# Generated by FakeRAM 2.0
VERSION 5.7 ;
BUSBITCHARS "[]" ;
PROPERTYDEFINITIONS
  MACRO width INTEGER ;
  MACRO depth INTEGER ;
  MACRO banks INTEGER ;
END PROPERTYDEFINITIONS
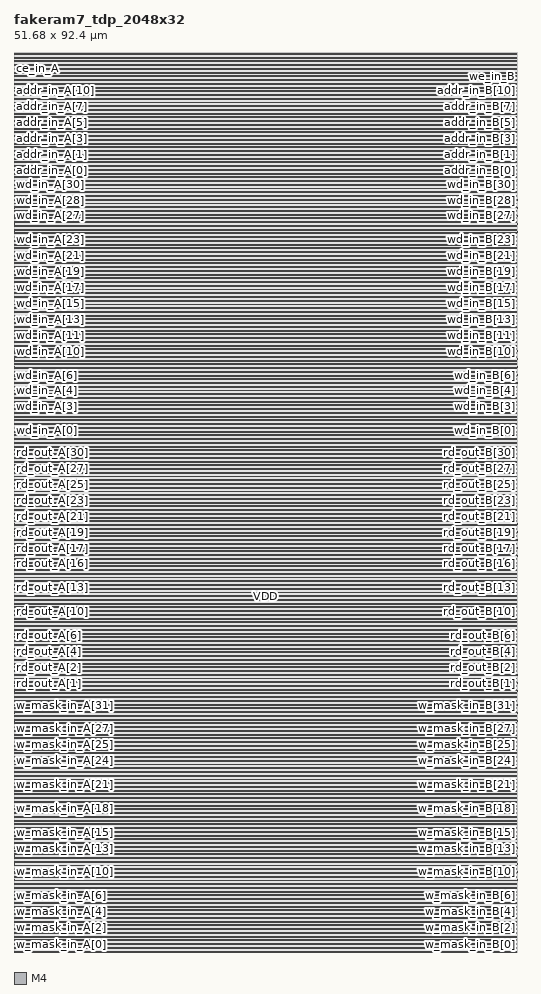
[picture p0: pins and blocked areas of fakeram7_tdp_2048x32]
MACRO fakeram7_tdp_2048x32
  PROPERTY width 32 ;
  PROPERTY depth 2048 ;
  PROPERTY banks 8 ;
  FOREIGN fakeram7_tdp_2048x32 0 0 ;
  SYMMETRY X Y ;
  SIZE 51.680 BY 92.400 ;
  CLASS BLOCK ;
  PIN w_mask_in_A[0]
    DIRECTION INPUT ;
    USE SIGNAL ;
    SHAPE ABUTMENT ;
    PORT
      LAYER M4 ;
      RECT 0.000 0.048 0.024 0.072 ;
    END
  END w_mask_in_A[0]
  PIN w_mask_in_B[0]
    DIRECTION INPUT ;
    USE SIGNAL ;
    SHAPE ABUTMENT ;
    PORT
      LAYER M4 ;
      RECT 51.656 0.048 51.680 0.072 ;
    END
  END w_mask_in_B[0]
  PIN w_mask_in_A[1]
    DIRECTION INPUT ;
    USE SIGNAL ;
    SHAPE ABUTMENT ;
    PORT
      LAYER M4 ;
      RECT 0.000 0.864 0.024 0.888 ;
    END
  END w_mask_in_A[1]
  PIN w_mask_in_B[1]
    DIRECTION INPUT ;
    USE SIGNAL ;
    SHAPE ABUTMENT ;
    PORT
      LAYER M4 ;
      RECT 51.656 0.864 51.680 0.888 ;
    END
  END w_mask_in_B[1]
  PIN w_mask_in_A[2]
    DIRECTION INPUT ;
    USE SIGNAL ;
    SHAPE ABUTMENT ;
    PORT
      LAYER M4 ;
      RECT 0.000 1.680 0.024 1.704 ;
    END
  END w_mask_in_A[2]
  PIN w_mask_in_B[2]
    DIRECTION INPUT ;
    USE SIGNAL ;
    SHAPE ABUTMENT ;
    PORT
      LAYER M4 ;
      RECT 51.656 1.680 51.680 1.704 ;
    END
  END w_mask_in_B[2]
  PIN w_mask_in_A[3]
    DIRECTION INPUT ;
    USE SIGNAL ;
    SHAPE ABUTMENT ;
    PORT
      LAYER M4 ;
      RECT 0.000 2.496 0.024 2.520 ;
    END
  END w_mask_in_A[3]
  PIN w_mask_in_B[3]
    DIRECTION INPUT ;
    USE SIGNAL ;
    SHAPE ABUTMENT ;
    PORT
      LAYER M4 ;
      RECT 51.656 2.496 51.680 2.520 ;
    END
  END w_mask_in_B[3]
  PIN w_mask_in_A[4]
    DIRECTION INPUT ;
    USE SIGNAL ;
    SHAPE ABUTMENT ;
    PORT
      LAYER M4 ;
      RECT 0.000 3.312 0.024 3.336 ;
    END
  END w_mask_in_A[4]
  PIN w_mask_in_B[4]
    DIRECTION INPUT ;
    USE SIGNAL ;
    SHAPE ABUTMENT ;
    PORT
      LAYER M4 ;
      RECT 51.656 3.312 51.680 3.336 ;
    END
  END w_mask_in_B[4]
  PIN w_mask_in_A[5]
    DIRECTION INPUT ;
    USE SIGNAL ;
    SHAPE ABUTMENT ;
    PORT
      LAYER M4 ;
      RECT 0.000 4.128 0.024 4.152 ;
    END
  END w_mask_in_A[5]
  PIN w_mask_in_B[5]
    DIRECTION INPUT ;
    USE SIGNAL ;
    SHAPE ABUTMENT ;
    PORT
      LAYER M4 ;
      RECT 51.656 4.128 51.680 4.152 ;
    END
  END w_mask_in_B[5]
  PIN w_mask_in_A[6]
    DIRECTION INPUT ;
    USE SIGNAL ;
    SHAPE ABUTMENT ;
    PORT
      LAYER M4 ;
      RECT 0.000 4.944 0.024 4.968 ;
    END
  END w_mask_in_A[6]
  PIN w_mask_in_B[6]
    DIRECTION INPUT ;
    USE SIGNAL ;
    SHAPE ABUTMENT ;
    PORT
      LAYER M4 ;
      RECT 51.656 4.944 51.680 4.968 ;
    END
  END w_mask_in_B[6]
  PIN w_mask_in_A[7]
    DIRECTION INPUT ;
    USE SIGNAL ;
    SHAPE ABUTMENT ;
    PORT
      LAYER M4 ;
      RECT 0.000 5.760 0.024 5.784 ;
    END
  END w_mask_in_A[7]
  PIN w_mask_in_B[7]
    DIRECTION INPUT ;
    USE SIGNAL ;
    SHAPE ABUTMENT ;
    PORT
      LAYER M4 ;
      RECT 51.656 5.760 51.680 5.784 ;
    END
  END w_mask_in_B[7]
  PIN w_mask_in_A[8]
    DIRECTION INPUT ;
    USE SIGNAL ;
    SHAPE ABUTMENT ;
    PORT
      LAYER M4 ;
      RECT 0.000 6.576 0.024 6.600 ;
    END
  END w_mask_in_A[8]
  PIN w_mask_in_B[8]
    DIRECTION INPUT ;
    USE SIGNAL ;
    SHAPE ABUTMENT ;
    PORT
      LAYER M4 ;
      RECT 51.656 6.576 51.680 6.600 ;
    END
  END w_mask_in_B[8]
  PIN w_mask_in_A[9]
    DIRECTION INPUT ;
    USE SIGNAL ;
    SHAPE ABUTMENT ;
    PORT
      LAYER M4 ;
      RECT 0.000 7.392 0.024 7.416 ;
    END
  END w_mask_in_A[9]
  PIN w_mask_in_B[9]
    DIRECTION INPUT ;
    USE SIGNAL ;
    SHAPE ABUTMENT ;
    PORT
      LAYER M4 ;
      RECT 51.656 7.392 51.680 7.416 ;
    END
  END w_mask_in_B[9]
  PIN w_mask_in_A[10]
    DIRECTION INPUT ;
    USE SIGNAL ;
    SHAPE ABUTMENT ;
    PORT
      LAYER M4 ;
      RECT 0.000 8.208 0.024 8.232 ;
    END
  END w_mask_in_A[10]
  PIN w_mask_in_B[10]
    DIRECTION INPUT ;
    USE SIGNAL ;
    SHAPE ABUTMENT ;
    PORT
      LAYER M4 ;
      RECT 51.656 8.208 51.680 8.232 ;
    END
  END w_mask_in_B[10]
  PIN w_mask_in_A[11]
    DIRECTION INPUT ;
    USE SIGNAL ;
    SHAPE ABUTMENT ;
    PORT
      LAYER M4 ;
      RECT 0.000 9.024 0.024 9.048 ;
    END
  END w_mask_in_A[11]
  PIN w_mask_in_B[11]
    DIRECTION INPUT ;
    USE SIGNAL ;
    SHAPE ABUTMENT ;
    PORT
      LAYER M4 ;
      RECT 51.656 9.024 51.680 9.048 ;
    END
  END w_mask_in_B[11]
  PIN w_mask_in_A[12]
    DIRECTION INPUT ;
    USE SIGNAL ;
    SHAPE ABUTMENT ;
    PORT
      LAYER M4 ;
      RECT 0.000 9.840 0.024 9.864 ;
    END
  END w_mask_in_A[12]
  PIN w_mask_in_B[12]
    DIRECTION INPUT ;
    USE SIGNAL ;
    SHAPE ABUTMENT ;
    PORT
      LAYER M4 ;
      RECT 51.656 9.840 51.680 9.864 ;
    END
  END w_mask_in_B[12]
  PIN w_mask_in_A[13]
    DIRECTION INPUT ;
    USE SIGNAL ;
    SHAPE ABUTMENT ;
    PORT
      LAYER M4 ;
      RECT 0.000 10.656 0.024 10.680 ;
    END
  END w_mask_in_A[13]
  PIN w_mask_in_B[13]
    DIRECTION INPUT ;
    USE SIGNAL ;
    SHAPE ABUTMENT ;
    PORT
      LAYER M4 ;
      RECT 51.656 10.656 51.680 10.680 ;
    END
  END w_mask_in_B[13]
  PIN w_mask_in_A[14]
    DIRECTION INPUT ;
    USE SIGNAL ;
    SHAPE ABUTMENT ;
    PORT
      LAYER M4 ;
      RECT 0.000 11.472 0.024 11.496 ;
    END
  END w_mask_in_A[14]
  PIN w_mask_in_B[14]
    DIRECTION INPUT ;
    USE SIGNAL ;
    SHAPE ABUTMENT ;
    PORT
      LAYER M4 ;
      RECT 51.656 11.472 51.680 11.496 ;
    END
  END w_mask_in_B[14]
  PIN w_mask_in_A[15]
    DIRECTION INPUT ;
    USE SIGNAL ;
    SHAPE ABUTMENT ;
    PORT
      LAYER M4 ;
      RECT 0.000 12.288 0.024 12.312 ;
    END
  END w_mask_in_A[15]
  PIN w_mask_in_B[15]
    DIRECTION INPUT ;
    USE SIGNAL ;
    SHAPE ABUTMENT ;
    PORT
      LAYER M4 ;
      RECT 51.656 12.288 51.680 12.312 ;
    END
  END w_mask_in_B[15]
  PIN w_mask_in_A[16]
    DIRECTION INPUT ;
    USE SIGNAL ;
    SHAPE ABUTMENT ;
    PORT
      LAYER M4 ;
      RECT 0.000 13.104 0.024 13.128 ;
    END
  END w_mask_in_A[16]
  PIN w_mask_in_B[16]
    DIRECTION INPUT ;
    USE SIGNAL ;
    SHAPE ABUTMENT ;
    PORT
      LAYER M4 ;
      RECT 51.656 13.104 51.680 13.128 ;
    END
  END w_mask_in_B[16]
  PIN w_mask_in_A[17]
    DIRECTION INPUT ;
    USE SIGNAL ;
    SHAPE ABUTMENT ;
    PORT
      LAYER M4 ;
      RECT 0.000 13.920 0.024 13.944 ;
    END
  END w_mask_in_A[17]
  PIN w_mask_in_B[17]
    DIRECTION INPUT ;
    USE SIGNAL ;
    SHAPE ABUTMENT ;
    PORT
      LAYER M4 ;
      RECT 51.656 13.920 51.680 13.944 ;
    END
  END w_mask_in_B[17]
  PIN w_mask_in_A[18]
    DIRECTION INPUT ;
    USE SIGNAL ;
    SHAPE ABUTMENT ;
    PORT
      LAYER M4 ;
      RECT 0.000 14.736 0.024 14.760 ;
    END
  END w_mask_in_A[18]
  PIN w_mask_in_B[18]
    DIRECTION INPUT ;
    USE SIGNAL ;
    SHAPE ABUTMENT ;
    PORT
      LAYER M4 ;
      RECT 51.656 14.736 51.680 14.760 ;
    END
  END w_mask_in_B[18]
  PIN w_mask_in_A[19]
    DIRECTION INPUT ;
    USE SIGNAL ;
    SHAPE ABUTMENT ;
    PORT
      LAYER M4 ;
      RECT 0.000 15.552 0.024 15.576 ;
    END
  END w_mask_in_A[19]
  PIN w_mask_in_B[19]
    DIRECTION INPUT ;
    USE SIGNAL ;
    SHAPE ABUTMENT ;
    PORT
      LAYER M4 ;
      RECT 51.656 15.552 51.680 15.576 ;
    END
  END w_mask_in_B[19]
  PIN w_mask_in_A[20]
    DIRECTION INPUT ;
    USE SIGNAL ;
    SHAPE ABUTMENT ;
    PORT
      LAYER M4 ;
      RECT 0.000 16.368 0.024 16.392 ;
    END
  END w_mask_in_A[20]
  PIN w_mask_in_B[20]
    DIRECTION INPUT ;
    USE SIGNAL ;
    SHAPE ABUTMENT ;
    PORT
      LAYER M4 ;
      RECT 51.656 16.368 51.680 16.392 ;
    END
  END w_mask_in_B[20]
  PIN w_mask_in_A[21]
    DIRECTION INPUT ;
    USE SIGNAL ;
    SHAPE ABUTMENT ;
    PORT
      LAYER M4 ;
      RECT 0.000 17.184 0.024 17.208 ;
    END
  END w_mask_in_A[21]
  PIN w_mask_in_B[21]
    DIRECTION INPUT ;
    USE SIGNAL ;
    SHAPE ABUTMENT ;
    PORT
      LAYER M4 ;
      RECT 51.656 17.184 51.680 17.208 ;
    END
  END w_mask_in_B[21]
  PIN w_mask_in_A[22]
    DIRECTION INPUT ;
    USE SIGNAL ;
    SHAPE ABUTMENT ;
    PORT
      LAYER M4 ;
      RECT 0.000 18.000 0.024 18.024 ;
    END
  END w_mask_in_A[22]
  PIN w_mask_in_B[22]
    DIRECTION INPUT ;
    USE SIGNAL ;
    SHAPE ABUTMENT ;
    PORT
      LAYER M4 ;
      RECT 51.656 18.000 51.680 18.024 ;
    END
  END w_mask_in_B[22]
  PIN w_mask_in_A[23]
    DIRECTION INPUT ;
    USE SIGNAL ;
    SHAPE ABUTMENT ;
    PORT
      LAYER M4 ;
      RECT 0.000 18.816 0.024 18.840 ;
    END
  END w_mask_in_A[23]
  PIN w_mask_in_B[23]
    DIRECTION INPUT ;
    USE SIGNAL ;
    SHAPE ABUTMENT ;
    PORT
      LAYER M4 ;
      RECT 51.656 18.816 51.680 18.840 ;
    END
  END w_mask_in_B[23]
  PIN w_mask_in_A[24]
    DIRECTION INPUT ;
    USE SIGNAL ;
    SHAPE ABUTMENT ;
    PORT
      LAYER M4 ;
      RECT 0.000 19.632 0.024 19.656 ;
    END
  END w_mask_in_A[24]
  PIN w_mask_in_B[24]
    DIRECTION INPUT ;
    USE SIGNAL ;
    SHAPE ABUTMENT ;
    PORT
      LAYER M4 ;
      RECT 51.656 19.632 51.680 19.656 ;
    END
  END w_mask_in_B[24]
  PIN w_mask_in_A[25]
    DIRECTION INPUT ;
    USE SIGNAL ;
    SHAPE ABUTMENT ;
    PORT
      LAYER M4 ;
      RECT 0.000 20.448 0.024 20.472 ;
    END
  END w_mask_in_A[25]
  PIN w_mask_in_B[25]
    DIRECTION INPUT ;
    USE SIGNAL ;
    SHAPE ABUTMENT ;
    PORT
      LAYER M4 ;
      RECT 51.656 20.448 51.680 20.472 ;
    END
  END w_mask_in_B[25]
  PIN w_mask_in_A[26]
    DIRECTION INPUT ;
    USE SIGNAL ;
    SHAPE ABUTMENT ;
    PORT
      LAYER M4 ;
      RECT 0.000 21.264 0.024 21.288 ;
    END
  END w_mask_in_A[26]
  PIN w_mask_in_B[26]
    DIRECTION INPUT ;
    USE SIGNAL ;
    SHAPE ABUTMENT ;
    PORT
      LAYER M4 ;
      RECT 51.656 21.264 51.680 21.288 ;
    END
  END w_mask_in_B[26]
  PIN w_mask_in_A[27]
    DIRECTION INPUT ;
    USE SIGNAL ;
    SHAPE ABUTMENT ;
    PORT
      LAYER M4 ;
      RECT 0.000 22.080 0.024 22.104 ;
    END
  END w_mask_in_A[27]
  PIN w_mask_in_B[27]
    DIRECTION INPUT ;
    USE SIGNAL ;
    SHAPE ABUTMENT ;
    PORT
      LAYER M4 ;
      RECT 51.656 22.080 51.680 22.104 ;
    END
  END w_mask_in_B[27]
  PIN w_mask_in_A[28]
    DIRECTION INPUT ;
    USE SIGNAL ;
    SHAPE ABUTMENT ;
    PORT
      LAYER M4 ;
      RECT 0.000 22.896 0.024 22.920 ;
    END
  END w_mask_in_A[28]
  PIN w_mask_in_B[28]
    DIRECTION INPUT ;
    USE SIGNAL ;
    SHAPE ABUTMENT ;
    PORT
      LAYER M4 ;
      RECT 51.656 22.896 51.680 22.920 ;
    END
  END w_mask_in_B[28]
  PIN w_mask_in_A[29]
    DIRECTION INPUT ;
    USE SIGNAL ;
    SHAPE ABUTMENT ;
    PORT
      LAYER M4 ;
      RECT 0.000 23.712 0.024 23.736 ;
    END
  END w_mask_in_A[29]
  PIN w_mask_in_B[29]
    DIRECTION INPUT ;
    USE SIGNAL ;
    SHAPE ABUTMENT ;
    PORT
      LAYER M4 ;
      RECT 51.656 23.712 51.680 23.736 ;
    END
  END w_mask_in_B[29]
  PIN w_mask_in_A[30]
    DIRECTION INPUT ;
    USE SIGNAL ;
    SHAPE ABUTMENT ;
    PORT
      LAYER M4 ;
      RECT 0.000 24.528 0.024 24.552 ;
    END
  END w_mask_in_A[30]
  PIN w_mask_in_B[30]
    DIRECTION INPUT ;
    USE SIGNAL ;
    SHAPE ABUTMENT ;
    PORT
      LAYER M4 ;
      RECT 51.656 24.528 51.680 24.552 ;
    END
  END w_mask_in_B[30]
  PIN w_mask_in_A[31]
    DIRECTION INPUT ;
    USE SIGNAL ;
    SHAPE ABUTMENT ;
    PORT
      LAYER M4 ;
      RECT 0.000 25.344 0.024 25.368 ;
    END
  END w_mask_in_A[31]
  PIN w_mask_in_B[31]
    DIRECTION INPUT ;
    USE SIGNAL ;
    SHAPE ABUTMENT ;
    PORT
      LAYER M4 ;
      RECT 51.656 25.344 51.680 25.368 ;
    END
  END w_mask_in_B[31]
  PIN rd_out_A[0]
    DIRECTION OUTPUT ;
    USE SIGNAL ;
    SHAPE ABUTMENT ;
    PORT
      LAYER M4 ;
      RECT 0.000 26.784 0.024 26.808 ;
    END
  END rd_out_A[0]
  PIN rd_out_B[0]
    DIRECTION OUTPUT ;
    USE SIGNAL ;
    SHAPE ABUTMENT ;
    PORT
      LAYER M4 ;
      RECT 51.656 26.784 51.680 26.808 ;
    END
  END rd_out_B[0]
  PIN rd_out_A[1]
    DIRECTION OUTPUT ;
    USE SIGNAL ;
    SHAPE ABUTMENT ;
    PORT
      LAYER M4 ;
      RECT 0.000 27.600 0.024 27.624 ;
    END
  END rd_out_A[1]
  PIN rd_out_B[1]
    DIRECTION OUTPUT ;
    USE SIGNAL ;
    SHAPE ABUTMENT ;
    PORT
      LAYER M4 ;
      RECT 51.656 27.600 51.680 27.624 ;
    END
  END rd_out_B[1]
  PIN rd_out_A[2]
    DIRECTION OUTPUT ;
    USE SIGNAL ;
    SHAPE ABUTMENT ;
    PORT
      LAYER M4 ;
      RECT 0.000 28.416 0.024 28.440 ;
    END
  END rd_out_A[2]
  PIN rd_out_B[2]
    DIRECTION OUTPUT ;
    USE SIGNAL ;
    SHAPE ABUTMENT ;
    PORT
      LAYER M4 ;
      RECT 51.656 28.416 51.680 28.440 ;
    END
  END rd_out_B[2]
  PIN rd_out_A[3]
    DIRECTION OUTPUT ;
    USE SIGNAL ;
    SHAPE ABUTMENT ;
    PORT
      LAYER M4 ;
      RECT 0.000 29.232 0.024 29.256 ;
    END
  END rd_out_A[3]
  PIN rd_out_B[3]
    DIRECTION OUTPUT ;
    USE SIGNAL ;
    SHAPE ABUTMENT ;
    PORT
      LAYER M4 ;
      RECT 51.656 29.232 51.680 29.256 ;
    END
  END rd_out_B[3]
  PIN rd_out_A[4]
    DIRECTION OUTPUT ;
    USE SIGNAL ;
    SHAPE ABUTMENT ;
    PORT
      LAYER M4 ;
      RECT 0.000 30.048 0.024 30.072 ;
    END
  END rd_out_A[4]
  PIN rd_out_B[4]
    DIRECTION OUTPUT ;
    USE SIGNAL ;
    SHAPE ABUTMENT ;
    PORT
      LAYER M4 ;
      RECT 51.656 30.048 51.680 30.072 ;
    END
  END rd_out_B[4]
  PIN rd_out_A[5]
    DIRECTION OUTPUT ;
    USE SIGNAL ;
    SHAPE ABUTMENT ;
    PORT
      LAYER M4 ;
      RECT 0.000 30.864 0.024 30.888 ;
    END
  END rd_out_A[5]
  PIN rd_out_B[5]
    DIRECTION OUTPUT ;
    USE SIGNAL ;
    SHAPE ABUTMENT ;
    PORT
      LAYER M4 ;
      RECT 51.656 30.864 51.680 30.888 ;
    END
  END rd_out_B[5]
  PIN rd_out_A[6]
    DIRECTION OUTPUT ;
    USE SIGNAL ;
    SHAPE ABUTMENT ;
    PORT
      LAYER M4 ;
      RECT 0.000 31.680 0.024 31.704 ;
    END
  END rd_out_A[6]
  PIN rd_out_B[6]
    DIRECTION OUTPUT ;
    USE SIGNAL ;
    SHAPE ABUTMENT ;
    PORT
      LAYER M4 ;
      RECT 51.656 31.680 51.680 31.704 ;
    END
  END rd_out_B[6]
  PIN rd_out_A[7]
    DIRECTION OUTPUT ;
    USE SIGNAL ;
    SHAPE ABUTMENT ;
    PORT
      LAYER M4 ;
      RECT 0.000 32.496 0.024 32.520 ;
    END
  END rd_out_A[7]
  PIN rd_out_B[7]
    DIRECTION OUTPUT ;
    USE SIGNAL ;
    SHAPE ABUTMENT ;
    PORT
      LAYER M4 ;
      RECT 51.656 32.496 51.680 32.520 ;
    END
  END rd_out_B[7]
  PIN rd_out_A[8]
    DIRECTION OUTPUT ;
    USE SIGNAL ;
    SHAPE ABUTMENT ;
    PORT
      LAYER M4 ;
      RECT 0.000 33.312 0.024 33.336 ;
    END
  END rd_out_A[8]
  PIN rd_out_B[8]
    DIRECTION OUTPUT ;
    USE SIGNAL ;
    SHAPE ABUTMENT ;
    PORT
      LAYER M4 ;
      RECT 51.656 33.312 51.680 33.336 ;
    END
  END rd_out_B[8]
  PIN rd_out_A[9]
    DIRECTION OUTPUT ;
    USE SIGNAL ;
    SHAPE ABUTMENT ;
    PORT
      LAYER M4 ;
      RECT 0.000 34.128 0.024 34.152 ;
    END
  END rd_out_A[9]
  PIN rd_out_B[9]
    DIRECTION OUTPUT ;
    USE SIGNAL ;
    SHAPE ABUTMENT ;
    PORT
      LAYER M4 ;
      RECT 51.656 34.128 51.680 34.152 ;
    END
  END rd_out_B[9]
  PIN rd_out_A[10]
    DIRECTION OUTPUT ;
    USE SIGNAL ;
    SHAPE ABUTMENT ;
    PORT
      LAYER M4 ;
      RECT 0.000 34.944 0.024 34.968 ;
    END
  END rd_out_A[10]
  PIN rd_out_B[10]
    DIRECTION OUTPUT ;
    USE SIGNAL ;
    SHAPE ABUTMENT ;
    PORT
      LAYER M4 ;
      RECT 51.656 34.944 51.680 34.968 ;
    END
  END rd_out_B[10]
  PIN rd_out_A[11]
    DIRECTION OUTPUT ;
    USE SIGNAL ;
    SHAPE ABUTMENT ;
    PORT
      LAYER M4 ;
      RECT 0.000 35.760 0.024 35.784 ;
    END
  END rd_out_A[11]
  PIN rd_out_B[11]
    DIRECTION OUTPUT ;
    USE SIGNAL ;
    SHAPE ABUTMENT ;
    PORT
      LAYER M4 ;
      RECT 51.656 35.760 51.680 35.784 ;
    END
  END rd_out_B[11]
  PIN rd_out_A[12]
    DIRECTION OUTPUT ;
    USE SIGNAL ;
    SHAPE ABUTMENT ;
    PORT
      LAYER M4 ;
      RECT 0.000 36.576 0.024 36.600 ;
    END
  END rd_out_A[12]
  PIN rd_out_B[12]
    DIRECTION OUTPUT ;
    USE SIGNAL ;
    SHAPE ABUTMENT ;
    PORT
      LAYER M4 ;
      RECT 51.656 36.576 51.680 36.600 ;
    END
  END rd_out_B[12]
  PIN rd_out_A[13]
    DIRECTION OUTPUT ;
    USE SIGNAL ;
    SHAPE ABUTMENT ;
    PORT
      LAYER M4 ;
      RECT 0.000 37.392 0.024 37.416 ;
    END
  END rd_out_A[13]
  PIN rd_out_B[13]
    DIRECTION OUTPUT ;
    USE SIGNAL ;
    SHAPE ABUTMENT ;
    PORT
      LAYER M4 ;
      RECT 51.656 37.392 51.680 37.416 ;
    END
  END rd_out_B[13]
  PIN rd_out_A[14]
    DIRECTION OUTPUT ;
    USE SIGNAL ;
    SHAPE ABUTMENT ;
    PORT
      LAYER M4 ;
      RECT 0.000 38.208 0.024 38.232 ;
    END
  END rd_out_A[14]
  PIN rd_out_B[14]
    DIRECTION OUTPUT ;
    USE SIGNAL ;
    SHAPE ABUTMENT ;
    PORT
      LAYER M4 ;
      RECT 51.656 38.208 51.680 38.232 ;
    END
  END rd_out_B[14]
  PIN rd_out_A[15]
    DIRECTION OUTPUT ;
    USE SIGNAL ;
    SHAPE ABUTMENT ;
    PORT
      LAYER M4 ;
      RECT 0.000 39.024 0.024 39.048 ;
    END
  END rd_out_A[15]
  PIN rd_out_B[15]
    DIRECTION OUTPUT ;
    USE SIGNAL ;
    SHAPE ABUTMENT ;
    PORT
      LAYER M4 ;
      RECT 51.656 39.024 51.680 39.048 ;
    END
  END rd_out_B[15]
  PIN rd_out_A[16]
    DIRECTION OUTPUT ;
    USE SIGNAL ;
    SHAPE ABUTMENT ;
    PORT
      LAYER M4 ;
      RECT 0.000 39.840 0.024 39.864 ;
    END
  END rd_out_A[16]
  PIN rd_out_B[16]
    DIRECTION OUTPUT ;
    USE SIGNAL ;
    SHAPE ABUTMENT ;
    PORT
      LAYER M4 ;
      RECT 51.656 39.840 51.680 39.864 ;
    END
  END rd_out_B[16]
  PIN rd_out_A[17]
    DIRECTION OUTPUT ;
    USE SIGNAL ;
    SHAPE ABUTMENT ;
    PORT
      LAYER M4 ;
      RECT 0.000 40.656 0.024 40.680 ;
    END
  END rd_out_A[17]
  PIN rd_out_B[17]
    DIRECTION OUTPUT ;
    USE SIGNAL ;
    SHAPE ABUTMENT ;
    PORT
      LAYER M4 ;
      RECT 51.656 40.656 51.680 40.680 ;
    END
  END rd_out_B[17]
  PIN rd_out_A[18]
    DIRECTION OUTPUT ;
    USE SIGNAL ;
    SHAPE ABUTMENT ;
    PORT
      LAYER M4 ;
      RECT 0.000 41.472 0.024 41.496 ;
    END
  END rd_out_A[18]
  PIN rd_out_B[18]
    DIRECTION OUTPUT ;
    USE SIGNAL ;
    SHAPE ABUTMENT ;
    PORT
      LAYER M4 ;
      RECT 51.656 41.472 51.680 41.496 ;
    END
  END rd_out_B[18]
  PIN rd_out_A[19]
    DIRECTION OUTPUT ;
    USE SIGNAL ;
    SHAPE ABUTMENT ;
    PORT
      LAYER M4 ;
      RECT 0.000 42.288 0.024 42.312 ;
    END
  END rd_out_A[19]
  PIN rd_out_B[19]
    DIRECTION OUTPUT ;
    USE SIGNAL ;
    SHAPE ABUTMENT ;
    PORT
      LAYER M4 ;
      RECT 51.656 42.288 51.680 42.312 ;
    END
  END rd_out_B[19]
  PIN rd_out_A[20]
    DIRECTION OUTPUT ;
    USE SIGNAL ;
    SHAPE ABUTMENT ;
    PORT
      LAYER M4 ;
      RECT 0.000 43.104 0.024 43.128 ;
    END
  END rd_out_A[20]
  PIN rd_out_B[20]
    DIRECTION OUTPUT ;
    USE SIGNAL ;
    SHAPE ABUTMENT ;
    PORT
      LAYER M4 ;
      RECT 51.656 43.104 51.680 43.128 ;
    END
  END rd_out_B[20]
  PIN rd_out_A[21]
    DIRECTION OUTPUT ;
    USE SIGNAL ;
    SHAPE ABUTMENT ;
    PORT
      LAYER M4 ;
      RECT 0.000 43.920 0.024 43.944 ;
    END
  END rd_out_A[21]
  PIN rd_out_B[21]
    DIRECTION OUTPUT ;
    USE SIGNAL ;
    SHAPE ABUTMENT ;
    PORT
      LAYER M4 ;
      RECT 51.656 43.920 51.680 43.944 ;
    END
  END rd_out_B[21]
  PIN rd_out_A[22]
    DIRECTION OUTPUT ;
    USE SIGNAL ;
    SHAPE ABUTMENT ;
    PORT
      LAYER M4 ;
      RECT 0.000 44.736 0.024 44.760 ;
    END
  END rd_out_A[22]
  PIN rd_out_B[22]
    DIRECTION OUTPUT ;
    USE SIGNAL ;
    SHAPE ABUTMENT ;
    PORT
      LAYER M4 ;
      RECT 51.656 44.736 51.680 44.760 ;
    END
  END rd_out_B[22]
  PIN rd_out_A[23]
    DIRECTION OUTPUT ;
    USE SIGNAL ;
    SHAPE ABUTMENT ;
    PORT
      LAYER M4 ;
      RECT 0.000 45.552 0.024 45.576 ;
    END
  END rd_out_A[23]
  PIN rd_out_B[23]
    DIRECTION OUTPUT ;
    USE SIGNAL ;
    SHAPE ABUTMENT ;
    PORT
      LAYER M4 ;
      RECT 51.656 45.552 51.680 45.576 ;
    END
  END rd_out_B[23]
  PIN rd_out_A[24]
    DIRECTION OUTPUT ;
    USE SIGNAL ;
    SHAPE ABUTMENT ;
    PORT
      LAYER M4 ;
      RECT 0.000 46.368 0.024 46.392 ;
    END
  END rd_out_A[24]
  PIN rd_out_B[24]
    DIRECTION OUTPUT ;
    USE SIGNAL ;
    SHAPE ABUTMENT ;
    PORT
      LAYER M4 ;
      RECT 51.656 46.368 51.680 46.392 ;
    END
  END rd_out_B[24]
  PIN rd_out_A[25]
    DIRECTION OUTPUT ;
    USE SIGNAL ;
    SHAPE ABUTMENT ;
    PORT
      LAYER M4 ;
      RECT 0.000 47.184 0.024 47.208 ;
    END
  END rd_out_A[25]
  PIN rd_out_B[25]
    DIRECTION OUTPUT ;
    USE SIGNAL ;
    SHAPE ABUTMENT ;
    PORT
      LAYER M4 ;
      RECT 51.656 47.184 51.680 47.208 ;
    END
  END rd_out_B[25]
  PIN rd_out_A[26]
    DIRECTION OUTPUT ;
    USE SIGNAL ;
    SHAPE ABUTMENT ;
    PORT
      LAYER M4 ;
      RECT 0.000 48.000 0.024 48.024 ;
    END
  END rd_out_A[26]
  PIN rd_out_B[26]
    DIRECTION OUTPUT ;
    USE SIGNAL ;
    SHAPE ABUTMENT ;
    PORT
      LAYER M4 ;
      RECT 51.656 48.000 51.680 48.024 ;
    END
  END rd_out_B[26]
  PIN rd_out_A[27]
    DIRECTION OUTPUT ;
    USE SIGNAL ;
    SHAPE ABUTMENT ;
    PORT
      LAYER M4 ;
      RECT 0.000 48.816 0.024 48.840 ;
    END
  END rd_out_A[27]
  PIN rd_out_B[27]
    DIRECTION OUTPUT ;
    USE SIGNAL ;
    SHAPE ABUTMENT ;
    PORT
      LAYER M4 ;
      RECT 51.656 48.816 51.680 48.840 ;
    END
  END rd_out_B[27]
  PIN rd_out_A[28]
    DIRECTION OUTPUT ;
    USE SIGNAL ;
    SHAPE ABUTMENT ;
    PORT
      LAYER M4 ;
      RECT 0.000 49.632 0.024 49.656 ;
    END
  END rd_out_A[28]
  PIN rd_out_B[28]
    DIRECTION OUTPUT ;
    USE SIGNAL ;
    SHAPE ABUTMENT ;
    PORT
      LAYER M4 ;
      RECT 51.656 49.632 51.680 49.656 ;
    END
  END rd_out_B[28]
  PIN rd_out_A[29]
    DIRECTION OUTPUT ;
    USE SIGNAL ;
    SHAPE ABUTMENT ;
    PORT
      LAYER M4 ;
      RECT 0.000 50.448 0.024 50.472 ;
    END
  END rd_out_A[29]
  PIN rd_out_B[29]
    DIRECTION OUTPUT ;
    USE SIGNAL ;
    SHAPE ABUTMENT ;
    PORT
      LAYER M4 ;
      RECT 51.656 50.448 51.680 50.472 ;
    END
  END rd_out_B[29]
  PIN rd_out_A[30]
    DIRECTION OUTPUT ;
    USE SIGNAL ;
    SHAPE ABUTMENT ;
    PORT
      LAYER M4 ;
      RECT 0.000 51.264 0.024 51.288 ;
    END
  END rd_out_A[30]
  PIN rd_out_B[30]
    DIRECTION OUTPUT ;
    USE SIGNAL ;
    SHAPE ABUTMENT ;
    PORT
      LAYER M4 ;
      RECT 51.656 51.264 51.680 51.288 ;
    END
  END rd_out_B[30]
  PIN rd_out_A[31]
    DIRECTION OUTPUT ;
    USE SIGNAL ;
    SHAPE ABUTMENT ;
    PORT
      LAYER M4 ;
      RECT 0.000 52.080 0.024 52.104 ;
    END
  END rd_out_A[31]
  PIN rd_out_B[31]
    DIRECTION OUTPUT ;
    USE SIGNAL ;
    SHAPE ABUTMENT ;
    PORT
      LAYER M4 ;
      RECT 51.656 52.080 51.680 52.104 ;
    END
  END rd_out_B[31]
  PIN wd_in_A[0]
    DIRECTION INPUT ;
    USE SIGNAL ;
    SHAPE ABUTMENT ;
    PORT
      LAYER M4 ;
      RECT 0.000 53.520 0.024 53.544 ;
    END
  END wd_in_A[0]
  PIN wd_in_B[0]
    DIRECTION INPUT ;
    USE SIGNAL ;
    SHAPE ABUTMENT ;
    PORT
      LAYER M4 ;
      RECT 51.656 53.520 51.680 53.544 ;
    END
  END wd_in_B[0]
  PIN wd_in_A[1]
    DIRECTION INPUT ;
    USE SIGNAL ;
    SHAPE ABUTMENT ;
    PORT
      LAYER M4 ;
      RECT 0.000 54.336 0.024 54.360 ;
    END
  END wd_in_A[1]
  PIN wd_in_B[1]
    DIRECTION INPUT ;
    USE SIGNAL ;
    SHAPE ABUTMENT ;
    PORT
      LAYER M4 ;
      RECT 51.656 54.336 51.680 54.360 ;
    END
  END wd_in_B[1]
  PIN wd_in_A[2]
    DIRECTION INPUT ;
    USE SIGNAL ;
    SHAPE ABUTMENT ;
    PORT
      LAYER M4 ;
      RECT 0.000 55.152 0.024 55.176 ;
    END
  END wd_in_A[2]
  PIN wd_in_B[2]
    DIRECTION INPUT ;
    USE SIGNAL ;
    SHAPE ABUTMENT ;
    PORT
      LAYER M4 ;
      RECT 51.656 55.152 51.680 55.176 ;
    END
  END wd_in_B[2]
  PIN wd_in_A[3]
    DIRECTION INPUT ;
    USE SIGNAL ;
    SHAPE ABUTMENT ;
    PORT
      LAYER M4 ;
      RECT 0.000 55.968 0.024 55.992 ;
    END
  END wd_in_A[3]
  PIN wd_in_B[3]
    DIRECTION INPUT ;
    USE SIGNAL ;
    SHAPE ABUTMENT ;
    PORT
      LAYER M4 ;
      RECT 51.656 55.968 51.680 55.992 ;
    END
  END wd_in_B[3]
  PIN wd_in_A[4]
    DIRECTION INPUT ;
    USE SIGNAL ;
    SHAPE ABUTMENT ;
    PORT
      LAYER M4 ;
      RECT 0.000 56.784 0.024 56.808 ;
    END
  END wd_in_A[4]
  PIN wd_in_B[4]
    DIRECTION INPUT ;
    USE SIGNAL ;
    SHAPE ABUTMENT ;
    PORT
      LAYER M4 ;
      RECT 51.656 56.784 51.680 56.808 ;
    END
  END wd_in_B[4]
  PIN wd_in_A[5]
    DIRECTION INPUT ;
    USE SIGNAL ;
    SHAPE ABUTMENT ;
    PORT
      LAYER M4 ;
      RECT 0.000 57.600 0.024 57.624 ;
    END
  END wd_in_A[5]
  PIN wd_in_B[5]
    DIRECTION INPUT ;
    USE SIGNAL ;
    SHAPE ABUTMENT ;
    PORT
      LAYER M4 ;
      RECT 51.656 57.600 51.680 57.624 ;
    END
  END wd_in_B[5]
  PIN wd_in_A[6]
    DIRECTION INPUT ;
    USE SIGNAL ;
    SHAPE ABUTMENT ;
    PORT
      LAYER M4 ;
      RECT 0.000 58.416 0.024 58.440 ;
    END
  END wd_in_A[6]
  PIN wd_in_B[6]
    DIRECTION INPUT ;
    USE SIGNAL ;
    SHAPE ABUTMENT ;
    PORT
      LAYER M4 ;
      RECT 51.656 58.416 51.680 58.440 ;
    END
  END wd_in_B[6]
  PIN wd_in_A[7]
    DIRECTION INPUT ;
    USE SIGNAL ;
    SHAPE ABUTMENT ;
    PORT
      LAYER M4 ;
      RECT 0.000 59.232 0.024 59.256 ;
    END
  END wd_in_A[7]
  PIN wd_in_B[7]
    DIRECTION INPUT ;
    USE SIGNAL ;
    SHAPE ABUTMENT ;
    PORT
      LAYER M4 ;
      RECT 51.656 59.232 51.680 59.256 ;
    END
  END wd_in_B[7]
  PIN wd_in_A[8]
    DIRECTION INPUT ;
    USE SIGNAL ;
    SHAPE ABUTMENT ;
    PORT
      LAYER M4 ;
      RECT 0.000 60.048 0.024 60.072 ;
    END
  END wd_in_A[8]
  PIN wd_in_B[8]
    DIRECTION INPUT ;
    USE SIGNAL ;
    SHAPE ABUTMENT ;
    PORT
      LAYER M4 ;
      RECT 51.656 60.048 51.680 60.072 ;
    END
  END wd_in_B[8]
  PIN wd_in_A[9]
    DIRECTION INPUT ;
    USE SIGNAL ;
    SHAPE ABUTMENT ;
    PORT
      LAYER M4 ;
      RECT 0.000 60.864 0.024 60.888 ;
    END
  END wd_in_A[9]
  PIN wd_in_B[9]
    DIRECTION INPUT ;
    USE SIGNAL ;
    SHAPE ABUTMENT ;
    PORT
      LAYER M4 ;
      RECT 51.656 60.864 51.680 60.888 ;
    END
  END wd_in_B[9]
  PIN wd_in_A[10]
    DIRECTION INPUT ;
    USE SIGNAL ;
    SHAPE ABUTMENT ;
    PORT
      LAYER M4 ;
      RECT 0.000 61.680 0.024 61.704 ;
    END
  END wd_in_A[10]
  PIN wd_in_B[10]
    DIRECTION INPUT ;
    USE SIGNAL ;
    SHAPE ABUTMENT ;
    PORT
      LAYER M4 ;
      RECT 51.656 61.680 51.680 61.704 ;
    END
  END wd_in_B[10]
  PIN wd_in_A[11]
    DIRECTION INPUT ;
    USE SIGNAL ;
    SHAPE ABUTMENT ;
    PORT
      LAYER M4 ;
      RECT 0.000 62.496 0.024 62.520 ;
    END
  END wd_in_A[11]
  PIN wd_in_B[11]
    DIRECTION INPUT ;
    USE SIGNAL ;
    SHAPE ABUTMENT ;
    PORT
      LAYER M4 ;
      RECT 51.656 62.496 51.680 62.520 ;
    END
  END wd_in_B[11]
  PIN wd_in_A[12]
    DIRECTION INPUT ;
    USE SIGNAL ;
    SHAPE ABUTMENT ;
    PORT
      LAYER M4 ;
      RECT 0.000 63.312 0.024 63.336 ;
    END
  END wd_in_A[12]
  PIN wd_in_B[12]
    DIRECTION INPUT ;
    USE SIGNAL ;
    SHAPE ABUTMENT ;
    PORT
      LAYER M4 ;
      RECT 51.656 63.312 51.680 63.336 ;
    END
  END wd_in_B[12]
  PIN wd_in_A[13]
    DIRECTION INPUT ;
    USE SIGNAL ;
    SHAPE ABUTMENT ;
    PORT
      LAYER M4 ;
      RECT 0.000 64.128 0.024 64.152 ;
    END
  END wd_in_A[13]
  PIN wd_in_B[13]
    DIRECTION INPUT ;
    USE SIGNAL ;
    SHAPE ABUTMENT ;
    PORT
      LAYER M4 ;
      RECT 51.656 64.128 51.680 64.152 ;
    END
  END wd_in_B[13]
  PIN wd_in_A[14]
    DIRECTION INPUT ;
    USE SIGNAL ;
    SHAPE ABUTMENT ;
    PORT
      LAYER M4 ;
      RECT 0.000 64.944 0.024 64.968 ;
    END
  END wd_in_A[14]
  PIN wd_in_B[14]
    DIRECTION INPUT ;
    USE SIGNAL ;
    SHAPE ABUTMENT ;
    PORT
      LAYER M4 ;
      RECT 51.656 64.944 51.680 64.968 ;
    END
  END wd_in_B[14]
  PIN wd_in_A[15]
    DIRECTION INPUT ;
    USE SIGNAL ;
    SHAPE ABUTMENT ;
    PORT
      LAYER M4 ;
      RECT 0.000 65.760 0.024 65.784 ;
    END
  END wd_in_A[15]
  PIN wd_in_B[15]
    DIRECTION INPUT ;
    USE SIGNAL ;
    SHAPE ABUTMENT ;
    PORT
      LAYER M4 ;
      RECT 51.656 65.760 51.680 65.784 ;
    END
  END wd_in_B[15]
  PIN wd_in_A[16]
    DIRECTION INPUT ;
    USE SIGNAL ;
    SHAPE ABUTMENT ;
    PORT
      LAYER M4 ;
      RECT 0.000 66.576 0.024 66.600 ;
    END
  END wd_in_A[16]
  PIN wd_in_B[16]
    DIRECTION INPUT ;
    USE SIGNAL ;
    SHAPE ABUTMENT ;
    PORT
      LAYER M4 ;
      RECT 51.656 66.576 51.680 66.600 ;
    END
  END wd_in_B[16]
  PIN wd_in_A[17]
    DIRECTION INPUT ;
    USE SIGNAL ;
    SHAPE ABUTMENT ;
    PORT
      LAYER M4 ;
      RECT 0.000 67.392 0.024 67.416 ;
    END
  END wd_in_A[17]
  PIN wd_in_B[17]
    DIRECTION INPUT ;
    USE SIGNAL ;
    SHAPE ABUTMENT ;
    PORT
      LAYER M4 ;
      RECT 51.656 67.392 51.680 67.416 ;
    END
  END wd_in_B[17]
  PIN wd_in_A[18]
    DIRECTION INPUT ;
    USE SIGNAL ;
    SHAPE ABUTMENT ;
    PORT
      LAYER M4 ;
      RECT 0.000 68.208 0.024 68.232 ;
    END
  END wd_in_A[18]
  PIN wd_in_B[18]
    DIRECTION INPUT ;
    USE SIGNAL ;
    SHAPE ABUTMENT ;
    PORT
      LAYER M4 ;
      RECT 51.656 68.208 51.680 68.232 ;
    END
  END wd_in_B[18]
  PIN wd_in_A[19]
    DIRECTION INPUT ;
    USE SIGNAL ;
    SHAPE ABUTMENT ;
    PORT
      LAYER M4 ;
      RECT 0.000 69.024 0.024 69.048 ;
    END
  END wd_in_A[19]
  PIN wd_in_B[19]
    DIRECTION INPUT ;
    USE SIGNAL ;
    SHAPE ABUTMENT ;
    PORT
      LAYER M4 ;
      RECT 51.656 69.024 51.680 69.048 ;
    END
  END wd_in_B[19]
  PIN wd_in_A[20]
    DIRECTION INPUT ;
    USE SIGNAL ;
    SHAPE ABUTMENT ;
    PORT
      LAYER M4 ;
      RECT 0.000 69.840 0.024 69.864 ;
    END
  END wd_in_A[20]
  PIN wd_in_B[20]
    DIRECTION INPUT ;
    USE SIGNAL ;
    SHAPE ABUTMENT ;
    PORT
      LAYER M4 ;
      RECT 51.656 69.840 51.680 69.864 ;
    END
  END wd_in_B[20]
  PIN wd_in_A[21]
    DIRECTION INPUT ;
    USE SIGNAL ;
    SHAPE ABUTMENT ;
    PORT
      LAYER M4 ;
      RECT 0.000 70.656 0.024 70.680 ;
    END
  END wd_in_A[21]
  PIN wd_in_B[21]
    DIRECTION INPUT ;
    USE SIGNAL ;
    SHAPE ABUTMENT ;
    PORT
      LAYER M4 ;
      RECT 51.656 70.656 51.680 70.680 ;
    END
  END wd_in_B[21]
  PIN wd_in_A[22]
    DIRECTION INPUT ;
    USE SIGNAL ;
    SHAPE ABUTMENT ;
    PORT
      LAYER M4 ;
      RECT 0.000 71.472 0.024 71.496 ;
    END
  END wd_in_A[22]
  PIN wd_in_B[22]
    DIRECTION INPUT ;
    USE SIGNAL ;
    SHAPE ABUTMENT ;
    PORT
      LAYER M4 ;
      RECT 51.656 71.472 51.680 71.496 ;
    END
  END wd_in_B[22]
  PIN wd_in_A[23]
    DIRECTION INPUT ;
    USE SIGNAL ;
    SHAPE ABUTMENT ;
    PORT
      LAYER M4 ;
      RECT 0.000 72.288 0.024 72.312 ;
    END
  END wd_in_A[23]
  PIN wd_in_B[23]
    DIRECTION INPUT ;
    USE SIGNAL ;
    SHAPE ABUTMENT ;
    PORT
      LAYER M4 ;
      RECT 51.656 72.288 51.680 72.312 ;
    END
  END wd_in_B[23]
  PIN wd_in_A[24]
    DIRECTION INPUT ;
    USE SIGNAL ;
    SHAPE ABUTMENT ;
    PORT
      LAYER M4 ;
      RECT 0.000 73.104 0.024 73.128 ;
    END
  END wd_in_A[24]
  PIN wd_in_B[24]
    DIRECTION INPUT ;
    USE SIGNAL ;
    SHAPE ABUTMENT ;
    PORT
      LAYER M4 ;
      RECT 51.656 73.104 51.680 73.128 ;
    END
  END wd_in_B[24]
  PIN wd_in_A[25]
    DIRECTION INPUT ;
    USE SIGNAL ;
    SHAPE ABUTMENT ;
    PORT
      LAYER M4 ;
      RECT 0.000 73.920 0.024 73.944 ;
    END
  END wd_in_A[25]
  PIN wd_in_B[25]
    DIRECTION INPUT ;
    USE SIGNAL ;
    SHAPE ABUTMENT ;
    PORT
      LAYER M4 ;
      RECT 51.656 73.920 51.680 73.944 ;
    END
  END wd_in_B[25]
  PIN wd_in_A[26]
    DIRECTION INPUT ;
    USE SIGNAL ;
    SHAPE ABUTMENT ;
    PORT
      LAYER M4 ;
      RECT 0.000 74.736 0.024 74.760 ;
    END
  END wd_in_A[26]
  PIN wd_in_B[26]
    DIRECTION INPUT ;
    USE SIGNAL ;
    SHAPE ABUTMENT ;
    PORT
      LAYER M4 ;
      RECT 51.656 74.736 51.680 74.760 ;
    END
  END wd_in_B[26]
  PIN wd_in_A[27]
    DIRECTION INPUT ;
    USE SIGNAL ;
    SHAPE ABUTMENT ;
    PORT
      LAYER M4 ;
      RECT 0.000 75.552 0.024 75.576 ;
    END
  END wd_in_A[27]
  PIN wd_in_B[27]
    DIRECTION INPUT ;
    USE SIGNAL ;
    SHAPE ABUTMENT ;
    PORT
      LAYER M4 ;
      RECT 51.656 75.552 51.680 75.576 ;
    END
  END wd_in_B[27]
  PIN wd_in_A[28]
    DIRECTION INPUT ;
    USE SIGNAL ;
    SHAPE ABUTMENT ;
    PORT
      LAYER M4 ;
      RECT 0.000 76.368 0.024 76.392 ;
    END
  END wd_in_A[28]
  PIN wd_in_B[28]
    DIRECTION INPUT ;
    USE SIGNAL ;
    SHAPE ABUTMENT ;
    PORT
      LAYER M4 ;
      RECT 51.656 76.368 51.680 76.392 ;
    END
  END wd_in_B[28]
  PIN wd_in_A[29]
    DIRECTION INPUT ;
    USE SIGNAL ;
    SHAPE ABUTMENT ;
    PORT
      LAYER M4 ;
      RECT 0.000 77.184 0.024 77.208 ;
    END
  END wd_in_A[29]
  PIN wd_in_B[29]
    DIRECTION INPUT ;
    USE SIGNAL ;
    SHAPE ABUTMENT ;
    PORT
      LAYER M4 ;
      RECT 51.656 77.184 51.680 77.208 ;
    END
  END wd_in_B[29]
  PIN wd_in_A[30]
    DIRECTION INPUT ;
    USE SIGNAL ;
    SHAPE ABUTMENT ;
    PORT
      LAYER M4 ;
      RECT 0.000 78.000 0.024 78.024 ;
    END
  END wd_in_A[30]
  PIN wd_in_B[30]
    DIRECTION INPUT ;
    USE SIGNAL ;
    SHAPE ABUTMENT ;
    PORT
      LAYER M4 ;
      RECT 51.656 78.000 51.680 78.024 ;
    END
  END wd_in_B[30]
  PIN wd_in_A[31]
    DIRECTION INPUT ;
    USE SIGNAL ;
    SHAPE ABUTMENT ;
    PORT
      LAYER M4 ;
      RECT 0.000 78.816 0.024 78.840 ;
    END
  END wd_in_A[31]
  PIN wd_in_B[31]
    DIRECTION INPUT ;
    USE SIGNAL ;
    SHAPE ABUTMENT ;
    PORT
      LAYER M4 ;
      RECT 51.656 78.816 51.680 78.840 ;
    END
  END wd_in_B[31]
  PIN addr_in_A[0]
    DIRECTION INPUT ;
    USE SIGNAL ;
    SHAPE ABUTMENT ;
    PORT
      LAYER M4 ;
      RECT 0.000 80.256 0.024 80.280 ;
    END
  END addr_in_A[0]
  PIN addr_in_B[0]
    DIRECTION INPUT ;
    USE SIGNAL ;
    SHAPE ABUTMENT ;
    PORT
      LAYER M4 ;
      RECT 51.656 80.256 51.680 80.280 ;
    END
  END addr_in_B[0]
  PIN addr_in_A[1]
    DIRECTION INPUT ;
    USE SIGNAL ;
    SHAPE ABUTMENT ;
    PORT
      LAYER M4 ;
      RECT 0.000 81.072 0.024 81.096 ;
    END
  END addr_in_A[1]
  PIN addr_in_B[1]
    DIRECTION INPUT ;
    USE SIGNAL ;
    SHAPE ABUTMENT ;
    PORT
      LAYER M4 ;
      RECT 51.656 81.072 51.680 81.096 ;
    END
  END addr_in_B[1]
  PIN addr_in_A[2]
    DIRECTION INPUT ;
    USE SIGNAL ;
    SHAPE ABUTMENT ;
    PORT
      LAYER M4 ;
      RECT 0.000 81.888 0.024 81.912 ;
    END
  END addr_in_A[2]
  PIN addr_in_B[2]
    DIRECTION INPUT ;
    USE SIGNAL ;
    SHAPE ABUTMENT ;
    PORT
      LAYER M4 ;
      RECT 51.656 81.888 51.680 81.912 ;
    END
  END addr_in_B[2]
  PIN addr_in_A[3]
    DIRECTION INPUT ;
    USE SIGNAL ;
    SHAPE ABUTMENT ;
    PORT
      LAYER M4 ;
      RECT 0.000 82.704 0.024 82.728 ;
    END
  END addr_in_A[3]
  PIN addr_in_B[3]
    DIRECTION INPUT ;
    USE SIGNAL ;
    SHAPE ABUTMENT ;
    PORT
      LAYER M4 ;
      RECT 51.656 82.704 51.680 82.728 ;
    END
  END addr_in_B[3]
  PIN addr_in_A[4]
    DIRECTION INPUT ;
    USE SIGNAL ;
    SHAPE ABUTMENT ;
    PORT
      LAYER M4 ;
      RECT 0.000 83.520 0.024 83.544 ;
    END
  END addr_in_A[4]
  PIN addr_in_B[4]
    DIRECTION INPUT ;
    USE SIGNAL ;
    SHAPE ABUTMENT ;
    PORT
      LAYER M4 ;
      RECT 51.656 83.520 51.680 83.544 ;
    END
  END addr_in_B[4]
  PIN addr_in_A[5]
    DIRECTION INPUT ;
    USE SIGNAL ;
    SHAPE ABUTMENT ;
    PORT
      LAYER M4 ;
      RECT 0.000 84.336 0.024 84.360 ;
    END
  END addr_in_A[5]
  PIN addr_in_B[5]
    DIRECTION INPUT ;
    USE SIGNAL ;
    SHAPE ABUTMENT ;
    PORT
      LAYER M4 ;
      RECT 51.656 84.336 51.680 84.360 ;
    END
  END addr_in_B[5]
  PIN addr_in_A[6]
    DIRECTION INPUT ;
    USE SIGNAL ;
    SHAPE ABUTMENT ;
    PORT
      LAYER M4 ;
      RECT 0.000 85.152 0.024 85.176 ;
    END
  END addr_in_A[6]
  PIN addr_in_B[6]
    DIRECTION INPUT ;
    USE SIGNAL ;
    SHAPE ABUTMENT ;
    PORT
      LAYER M4 ;
      RECT 51.656 85.152 51.680 85.176 ;
    END
  END addr_in_B[6]
  PIN addr_in_A[7]
    DIRECTION INPUT ;
    USE SIGNAL ;
    SHAPE ABUTMENT ;
    PORT
      LAYER M4 ;
      RECT 0.000 85.968 0.024 85.992 ;
    END
  END addr_in_A[7]
  PIN addr_in_B[7]
    DIRECTION INPUT ;
    USE SIGNAL ;
    SHAPE ABUTMENT ;
    PORT
      LAYER M4 ;
      RECT 51.656 85.968 51.680 85.992 ;
    END
  END addr_in_B[7]
  PIN addr_in_A[8]
    DIRECTION INPUT ;
    USE SIGNAL ;
    SHAPE ABUTMENT ;
    PORT
      LAYER M4 ;
      RECT 0.000 86.784 0.024 86.808 ;
    END
  END addr_in_A[8]
  PIN addr_in_B[8]
    DIRECTION INPUT ;
    USE SIGNAL ;
    SHAPE ABUTMENT ;
    PORT
      LAYER M4 ;
      RECT 51.656 86.784 51.680 86.808 ;
    END
  END addr_in_B[8]
  PIN addr_in_A[9]
    DIRECTION INPUT ;
    USE SIGNAL ;
    SHAPE ABUTMENT ;
    PORT
      LAYER M4 ;
      RECT 0.000 87.600 0.024 87.624 ;
    END
  END addr_in_A[9]
  PIN addr_in_B[9]
    DIRECTION INPUT ;
    USE SIGNAL ;
    SHAPE ABUTMENT ;
    PORT
      LAYER M4 ;
      RECT 51.656 87.600 51.680 87.624 ;
    END
  END addr_in_B[9]
  PIN addr_in_A[10]
    DIRECTION INPUT ;
    USE SIGNAL ;
    SHAPE ABUTMENT ;
    PORT
      LAYER M4 ;
      RECT 0.000 88.416 0.024 88.440 ;
    END
  END addr_in_A[10]
  PIN addr_in_B[10]
    DIRECTION INPUT ;
    USE SIGNAL ;
    SHAPE ABUTMENT ;
    PORT
      LAYER M4 ;
      RECT 51.656 88.416 51.680 88.440 ;
    END
  END addr_in_B[10]
  PIN we_in_A
    DIRECTION INPUT ;
    USE SIGNAL ;
    SHAPE ABUTMENT ;
    PORT
      LAYER M4 ;
      RECT 0.000 89.856 0.024 89.880 ;
    END
  END we_in_A
  PIN we_in_B
    DIRECTION INPUT ;
    USE SIGNAL ;
    SHAPE ABUTMENT ;
    PORT
      LAYER M4 ;
      RECT 51.656 89.856 51.680 89.880 ;
    END
  END we_in_B
  PIN ce_in_A
    DIRECTION INPUT ;
    USE SIGNAL ;
    SHAPE ABUTMENT ;
    PORT
      LAYER M4 ;
      RECT 0.000 90.672 0.024 90.696 ;
    END
  END ce_in_A
  PIN clk_A
    DIRECTION INPUT ;
    USE SIGNAL ;
    SHAPE ABUTMENT ;
    PORT
      LAYER M4 ;
      RECT 0.000 91.488 0.024 91.512 ;
    END
  END clk_A
  PIN ce_in_B
    DIRECTION INPUT ;
    USE SIGNAL ;
    SHAPE ABUTMENT ;
    PORT
      LAYER M4 ;
      RECT 0.000 92.304 0.024 92.328 ;
    END
  END ce_in_B
  PIN clk_B
    DIRECTION INPUT ;
    USE SIGNAL ;
    SHAPE ABUTMENT ;
    PORT
      LAYER M4 ;
      RECT 0.000 93.120 0.024 93.144 ;
    END
  END clk_B
  PIN VSS
    DIRECTION INOUT ;
    USE GROUND ;
    PORT
      LAYER M4 ;
      RECT 0.048 0.000 51.632 0.096 ;
      RECT 0.048 0.768 51.632 0.864 ;
      RECT 0.048 1.536 51.632 1.632 ;
      RECT 0.048 2.304 51.632 2.400 ;
      RECT 0.048 3.072 51.632 3.168 ;
      RECT 0.048 3.840 51.632 3.936 ;
      RECT 0.048 4.608 51.632 4.704 ;
      RECT 0.048 5.376 51.632 5.472 ;
      RECT 0.048 6.144 51.632 6.240 ;
      RECT 0.048 6.912 51.632 7.008 ;
      RECT 0.048 7.680 51.632 7.776 ;
      RECT 0.048 8.448 51.632 8.544 ;
      RECT 0.048 9.216 51.632 9.312 ;
      RECT 0.048 9.984 51.632 10.080 ;
      RECT 0.048 10.752 51.632 10.848 ;
      RECT 0.048 11.520 51.632 11.616 ;
      RECT 0.048 12.288 51.632 12.384 ;
      RECT 0.048 13.056 51.632 13.152 ;
      RECT 0.048 13.824 51.632 13.920 ;
      RECT 0.048 14.592 51.632 14.688 ;
      RECT 0.048 15.360 51.632 15.456 ;
      RECT 0.048 16.128 51.632 16.224 ;
      RECT 0.048 16.896 51.632 16.992 ;
      RECT 0.048 17.664 51.632 17.760 ;
      RECT 0.048 18.432 51.632 18.528 ;
      RECT 0.048 19.200 51.632 19.296 ;
      RECT 0.048 19.968 51.632 20.064 ;
      RECT 0.048 20.736 51.632 20.832 ;
      RECT 0.048 21.504 51.632 21.600 ;
      RECT 0.048 22.272 51.632 22.368 ;
      RECT 0.048 23.040 51.632 23.136 ;
      RECT 0.048 23.808 51.632 23.904 ;
      RECT 0.048 24.576 51.632 24.672 ;
      RECT 0.048 25.344 51.632 25.440 ;
      RECT 0.048 26.112 51.632 26.208 ;
      RECT 0.048 26.880 51.632 26.976 ;
      RECT 0.048 27.648 51.632 27.744 ;
      RECT 0.048 28.416 51.632 28.512 ;
      RECT 0.048 29.184 51.632 29.280 ;
      RECT 0.048 29.952 51.632 30.048 ;
      RECT 0.048 30.720 51.632 30.816 ;
      RECT 0.048 31.488 51.632 31.584 ;
      RECT 0.048 32.256 51.632 32.352 ;
      RECT 0.048 33.024 51.632 33.120 ;
      RECT 0.048 33.792 51.632 33.888 ;
      RECT 0.048 34.560 51.632 34.656 ;
      RECT 0.048 35.328 51.632 35.424 ;
      RECT 0.048 36.096 51.632 36.192 ;
      RECT 0.048 36.864 51.632 36.960 ;
      RECT 0.048 37.632 51.632 37.728 ;
      RECT 0.048 38.400 51.632 38.496 ;
      RECT 0.048 39.168 51.632 39.264 ;
      RECT 0.048 39.936 51.632 40.032 ;
      RECT 0.048 40.704 51.632 40.800 ;
      RECT 0.048 41.472 51.632 41.568 ;
      RECT 0.048 42.240 51.632 42.336 ;
      RECT 0.048 43.008 51.632 43.104 ;
      RECT 0.048 43.776 51.632 43.872 ;
      RECT 0.048 44.544 51.632 44.640 ;
      RECT 0.048 45.312 51.632 45.408 ;
      RECT 0.048 46.080 51.632 46.176 ;
      RECT 0.048 46.848 51.632 46.944 ;
      RECT 0.048 47.616 51.632 47.712 ;
      RECT 0.048 48.384 51.632 48.480 ;
      RECT 0.048 49.152 51.632 49.248 ;
      RECT 0.048 49.920 51.632 50.016 ;
      RECT 0.048 50.688 51.632 50.784 ;
      RECT 0.048 51.456 51.632 51.552 ;
      RECT 0.048 52.224 51.632 52.320 ;
      RECT 0.048 52.992 51.632 53.088 ;
      RECT 0.048 53.760 51.632 53.856 ;
      RECT 0.048 54.528 51.632 54.624 ;
      RECT 0.048 55.296 51.632 55.392 ;
      RECT 0.048 56.064 51.632 56.160 ;
      RECT 0.048 56.832 51.632 56.928 ;
      RECT 0.048 57.600 51.632 57.696 ;
      RECT 0.048 58.368 51.632 58.464 ;
      RECT 0.048 59.136 51.632 59.232 ;
      RECT 0.048 59.904 51.632 60.000 ;
      RECT 0.048 60.672 51.632 60.768 ;
      RECT 0.048 61.440 51.632 61.536 ;
      RECT 0.048 62.208 51.632 62.304 ;
      RECT 0.048 62.976 51.632 63.072 ;
      RECT 0.048 63.744 51.632 63.840 ;
      RECT 0.048 64.512 51.632 64.608 ;
      RECT 0.048 65.280 51.632 65.376 ;
      RECT 0.048 66.048 51.632 66.144 ;
      RECT 0.048 66.816 51.632 66.912 ;
      RECT 0.048 67.584 51.632 67.680 ;
      RECT 0.048 68.352 51.632 68.448 ;
      RECT 0.048 69.120 51.632 69.216 ;
      RECT 0.048 69.888 51.632 69.984 ;
      RECT 0.048 70.656 51.632 70.752 ;
      RECT 0.048 71.424 51.632 71.520 ;
      RECT 0.048 72.192 51.632 72.288 ;
      RECT 0.048 72.960 51.632 73.056 ;
      RECT 0.048 73.728 51.632 73.824 ;
      RECT 0.048 74.496 51.632 74.592 ;
      RECT 0.048 75.264 51.632 75.360 ;
      RECT 0.048 76.032 51.632 76.128 ;
      RECT 0.048 76.800 51.632 76.896 ;
      RECT 0.048 77.568 51.632 77.664 ;
      RECT 0.048 78.336 51.632 78.432 ;
      RECT 0.048 79.104 51.632 79.200 ;
      RECT 0.048 79.872 51.632 79.968 ;
      RECT 0.048 80.640 51.632 80.736 ;
      RECT 0.048 81.408 51.632 81.504 ;
      RECT 0.048 82.176 51.632 82.272 ;
      RECT 0.048 82.944 51.632 83.040 ;
      RECT 0.048 83.712 51.632 83.808 ;
      RECT 0.048 84.480 51.632 84.576 ;
      RECT 0.048 85.248 51.632 85.344 ;
      RECT 0.048 86.016 51.632 86.112 ;
      RECT 0.048 86.784 51.632 86.880 ;
      RECT 0.048 87.552 51.632 87.648 ;
      RECT 0.048 88.320 51.632 88.416 ;
      RECT 0.048 89.088 51.632 89.184 ;
      RECT 0.048 89.856 51.632 89.952 ;
      RECT 0.048 90.624 51.632 90.720 ;
      RECT 0.048 91.392 51.632 91.488 ;
      RECT 0.048 92.160 51.632 92.256 ;
    END
  END VSS
  PIN VDD
    DIRECTION INOUT ;
    USE POWER ;
    PORT
      LAYER M4 ;
      RECT 0.048 0.384 51.632 0.480 ;
      RECT 0.048 1.152 51.632 1.248 ;
      RECT 0.048 1.920 51.632 2.016 ;
      RECT 0.048 2.688 51.632 2.784 ;
      RECT 0.048 3.456 51.632 3.552 ;
      RECT 0.048 4.224 51.632 4.320 ;
      RECT 0.048 4.992 51.632 5.088 ;
      RECT 0.048 5.760 51.632 5.856 ;
      RECT 0.048 6.528 51.632 6.624 ;
      RECT 0.048 7.296 51.632 7.392 ;
      RECT 0.048 8.064 51.632 8.160 ;
      RECT 0.048 8.832 51.632 8.928 ;
      RECT 0.048 9.600 51.632 9.696 ;
      RECT 0.048 10.368 51.632 10.464 ;
      RECT 0.048 11.136 51.632 11.232 ;
      RECT 0.048 11.904 51.632 12.000 ;
      RECT 0.048 12.672 51.632 12.768 ;
      RECT 0.048 13.440 51.632 13.536 ;
      RECT 0.048 14.208 51.632 14.304 ;
      RECT 0.048 14.976 51.632 15.072 ;
      RECT 0.048 15.744 51.632 15.840 ;
      RECT 0.048 16.512 51.632 16.608 ;
      RECT 0.048 17.280 51.632 17.376 ;
      RECT 0.048 18.048 51.632 18.144 ;
      RECT 0.048 18.816 51.632 18.912 ;
      RECT 0.048 19.584 51.632 19.680 ;
      RECT 0.048 20.352 51.632 20.448 ;
      RECT 0.048 21.120 51.632 21.216 ;
      RECT 0.048 21.888 51.632 21.984 ;
      RECT 0.048 22.656 51.632 22.752 ;
      RECT 0.048 23.424 51.632 23.520 ;
      RECT 0.048 24.192 51.632 24.288 ;
      RECT 0.048 24.960 51.632 25.056 ;
      RECT 0.048 25.728 51.632 25.824 ;
      RECT 0.048 26.496 51.632 26.592 ;
      RECT 0.048 27.264 51.632 27.360 ;
      RECT 0.048 28.032 51.632 28.128 ;
      RECT 0.048 28.800 51.632 28.896 ;
      RECT 0.048 29.568 51.632 29.664 ;
      RECT 0.048 30.336 51.632 30.432 ;
      RECT 0.048 31.104 51.632 31.200 ;
      RECT 0.048 31.872 51.632 31.968 ;
      RECT 0.048 32.640 51.632 32.736 ;
      RECT 0.048 33.408 51.632 33.504 ;
      RECT 0.048 34.176 51.632 34.272 ;
      RECT 0.048 34.944 51.632 35.040 ;
      RECT 0.048 35.712 51.632 35.808 ;
      RECT 0.048 36.480 51.632 36.576 ;
      RECT 0.048 37.248 51.632 37.344 ;
      RECT 0.048 38.016 51.632 38.112 ;
      RECT 0.048 38.784 51.632 38.880 ;
      RECT 0.048 39.552 51.632 39.648 ;
      RECT 0.048 40.320 51.632 40.416 ;
      RECT 0.048 41.088 51.632 41.184 ;
      RECT 0.048 41.856 51.632 41.952 ;
      RECT 0.048 42.624 51.632 42.720 ;
      RECT 0.048 43.392 51.632 43.488 ;
      RECT 0.048 44.160 51.632 44.256 ;
      RECT 0.048 44.928 51.632 45.024 ;
      RECT 0.048 45.696 51.632 45.792 ;
      RECT 0.048 46.464 51.632 46.560 ;
      RECT 0.048 47.232 51.632 47.328 ;
      RECT 0.048 48.000 51.632 48.096 ;
      RECT 0.048 48.768 51.632 48.864 ;
      RECT 0.048 49.536 51.632 49.632 ;
      RECT 0.048 50.304 51.632 50.400 ;
      RECT 0.048 51.072 51.632 51.168 ;
      RECT 0.048 51.840 51.632 51.936 ;
      RECT 0.048 52.608 51.632 52.704 ;
      RECT 0.048 53.376 51.632 53.472 ;
      RECT 0.048 54.144 51.632 54.240 ;
      RECT 0.048 54.912 51.632 55.008 ;
      RECT 0.048 55.680 51.632 55.776 ;
      RECT 0.048 56.448 51.632 56.544 ;
      RECT 0.048 57.216 51.632 57.312 ;
      RECT 0.048 57.984 51.632 58.080 ;
      RECT 0.048 58.752 51.632 58.848 ;
      RECT 0.048 59.520 51.632 59.616 ;
      RECT 0.048 60.288 51.632 60.384 ;
      RECT 0.048 61.056 51.632 61.152 ;
      RECT 0.048 61.824 51.632 61.920 ;
      RECT 0.048 62.592 51.632 62.688 ;
      RECT 0.048 63.360 51.632 63.456 ;
      RECT 0.048 64.128 51.632 64.224 ;
      RECT 0.048 64.896 51.632 64.992 ;
      RECT 0.048 65.664 51.632 65.760 ;
      RECT 0.048 66.432 51.632 66.528 ;
      RECT 0.048 67.200 51.632 67.296 ;
      RECT 0.048 67.968 51.632 68.064 ;
      RECT 0.048 68.736 51.632 68.832 ;
      RECT 0.048 69.504 51.632 69.600 ;
      RECT 0.048 70.272 51.632 70.368 ;
      RECT 0.048 71.040 51.632 71.136 ;
      RECT 0.048 71.808 51.632 71.904 ;
      RECT 0.048 72.576 51.632 72.672 ;
      RECT 0.048 73.344 51.632 73.440 ;
      RECT 0.048 74.112 51.632 74.208 ;
      RECT 0.048 74.880 51.632 74.976 ;
      RECT 0.048 75.648 51.632 75.744 ;
      RECT 0.048 76.416 51.632 76.512 ;
      RECT 0.048 77.184 51.632 77.280 ;
      RECT 0.048 77.952 51.632 78.048 ;
      RECT 0.048 78.720 51.632 78.816 ;
      RECT 0.048 79.488 51.632 79.584 ;
      RECT 0.048 80.256 51.632 80.352 ;
      RECT 0.048 81.024 51.632 81.120 ;
      RECT 0.048 81.792 51.632 81.888 ;
      RECT 0.048 82.560 51.632 82.656 ;
      RECT 0.048 83.328 51.632 83.424 ;
      RECT 0.048 84.096 51.632 84.192 ;
      RECT 0.048 84.864 51.632 84.960 ;
      RECT 0.048 85.632 51.632 85.728 ;
      RECT 0.048 86.400 51.632 86.496 ;
      RECT 0.048 87.168 51.632 87.264 ;
      RECT 0.048 87.936 51.632 88.032 ;
      RECT 0.048 88.704 51.632 88.800 ;
      RECT 0.048 89.472 51.632 89.568 ;
      RECT 0.048 90.240 51.632 90.336 ;
      RECT 0.048 91.008 51.632 91.104 ;
      RECT 0.048 91.776 51.632 91.872 ;
    END
  END VDD
  OBS
    LAYER M1 ;
    RECT 0 0 51.680 92.400 ;
    LAYER M2 ;
    RECT 0 0 51.680 92.400 ;
    LAYER M3 ;
    RECT 0 0 51.680 92.400 ;
    LAYER M4 ;
    RECT 0 0 51.680 92.400 ;
  END
END fakeram7_tdp_2048x32

END LIBRARY
